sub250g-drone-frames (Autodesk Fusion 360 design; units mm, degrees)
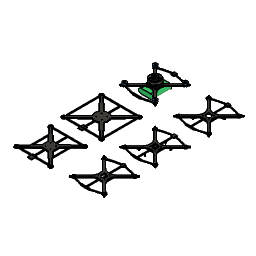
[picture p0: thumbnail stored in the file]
derived_base_feature "Derived Base Feature" bodies "Test Frame nr.3 (160mm) (1)", "Test Frame nr.4 (160mm) (1)", "Test Frame nr.5 (160mm)", "Test Frame nr.1 (200mm)", "FC (1)", "Test Frame nr.2 (180mm)", "RB 1202.5 11500KV Motor 1", "RB 1202.5 11500KV Motor 2"
named bodies: "Test Frame nr.3 (160mm) (1)", "Test Frame nr.4 (160mm) (1)", "Test Frame nr.5 (160mm)", "Test Frame nr.1 (200mm)", "FC (1)", "Test Frame nr.2 (180mm)", "RB 1202.5 11500KV Motor 1", "RB 1202.5 11500KV Motor 2", "RB 1202.5 11500KV Motor 4", "RB 1202.5 11500KV Motor 3", "Battery", "Carbon Frame", "LED Ring Stack Cover"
